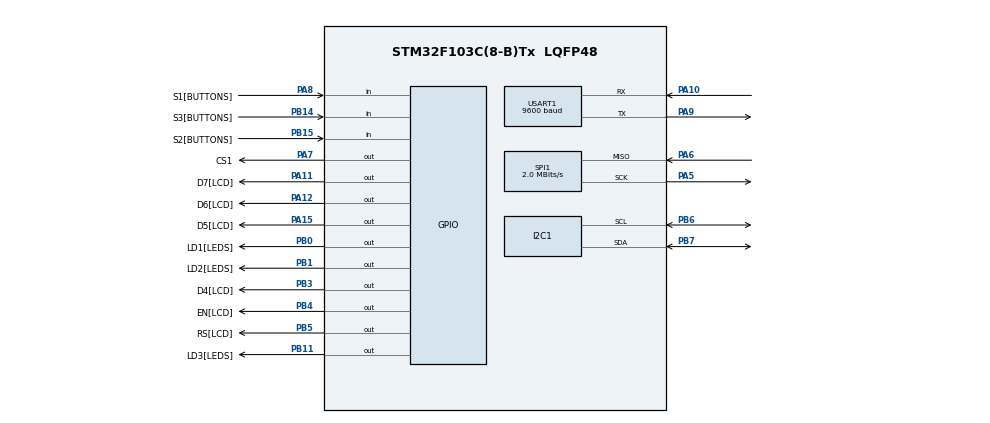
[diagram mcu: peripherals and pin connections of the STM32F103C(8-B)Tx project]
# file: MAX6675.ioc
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I2C1.I2C_Mode=I2C_Standard
Mcu.Family=STM32F1
Mcu.Name=STM32F103C(8-B)Tx
Mcu.Package=LQFP48
NVIC.PriorityGroup=NVIC_PRIORITYGROUP_4
PA10.Mode=Asynchronous
PA10.Signal=USART1_RX
PA11.GPIO_Label=D7[LCD]
PA11.Signal=GPIO_Output
PA12.GPIO_Label=D6[LCD]
PA12.Signal=GPIO_Output
PA13.Mode=Serial_Wire
PA13.Signal=SYS_JTMS-SWDIO
PA14.Mode=Serial_Wire
PA14.Signal=SYS_JTCK-SWCLK
PA15.GPIO_Label=D5[LCD]
PA15.Signal=GPIO_Output
PA5.Mode=RX_Only_Simplex_Unidirect_Master
PA5.Signal=SPI1_SCK
PA6.Mode=RX_Only_Simplex_Unidirect_Master
PA6.Signal=SPI1_MISO
PA7.GPIO_Label=CS1
PA7.Signal=GPIO_Output
PA8.GPIO_Label=S1[BUTTONS]
PA8.Signal=GPIO_Input
PA9.Mode=Asynchronous
PA9.Signal=USART1_TX
PB0.GPIO_Label=LD1[LEDS]
PB0.Signal=GPIO_Output
PB1.GPIO_Label=LD2[LEDS]
PB1.Signal=GPIO_Output
PB11.GPIO_Label=LD3[LEDS]
PB11.Signal=GPIO_Output
PB14.GPIO_Label=S3[BUTTONS]
PB14.Signal=GPIO_Input
PB15.GPIO_Label=S2[BUTTONS]
PB15.Signal=GPIO_Input
PB3.GPIO_Label=D4[LCD]
PB3.Signal=GPIO_Output
PB4.GPIO_Label=EN[LCD]
PB4.Signal=GPIO_Output
PB5.GPIO_Label=RS[LCD]
PB5.Signal=GPIO_Output
PB6.Mode=I2C
PB6.Signal=I2C1_SCL
PB7.Mode=I2C
PB7.Signal=I2C1_SDA
ProjectManager.HeapSize=0x200
ProjectManager.StackSize=0x400
ProjectManager.TargetToolchain=TrueSTUDIO
RCC.AHBFreq_Value=8000000
RCC.APB1Freq_Value=8000000
RCC.APB1TimFreq_Value=8000000
RCC.APB2CLKDivider=RCC_HCLK_DIV2
RCC.APB2Freq_Value=4000000
RCC.APB2TimFreq_Value=8000000
RCC.HCLKFreq_Value=8000000
RCC.PLLMUL=RCC_PLL_MUL9
RCC.SYSCLKFreq_VALUE=8000000
RCC.USBFreq_Value=36000000
SPI1.CLKPhase=SPI_PHASE_1EDGE
SPI1.CLKPolarity=SPI_POLARITY_LOW
SPI1.CalculateBaudRate=2.0 MBits/s
SPI1.DataSize=SPI_DATASIZE_8BIT
SPI1.Direction=SPI_DIRECTION_2LINES_RXONLY
SPI1.FirstBit=SPI_FIRSTBIT_LSB
SPI1.Mode=SPI_MODE_MASTER
SPI1.VirtualType=VM_MASTER
USART1.BaudRate=9600
USART1.VirtualMode=VM_ASYNC
board=MAX6675

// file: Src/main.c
/**
  ******************************************************************************
  * @file           : main.c
  * @brief          : Main program body
  ******************************************************************************
  ** This notice applies to any and all portions of this file
  * that are not between comment pairs USER CODE BEGIN and
  * USER CODE END. Other portions of this file, whether
  * inserted by the user or by software development tools
  * are owned by their respective copyright owners.
  *
  * COPYRIGHT(c) 2018 STMicroelectronics
  *
  * Redistribution and use in source and binary forms, with or without modification,
  * are permitted provided that the following conditions are met:
  *   1. Redistributions of source code must retain the above copyright notice,
  *      this list of conditions and the following disclaimer.
  *   2. Redistributions in binary form must reproduce the above copyright notice,
  *      this list of conditions and the following disclaimer in the documentation
  *      and/or other materials provided with the distribution.
  *   3. Neither the name of STMicroelectronics nor the names of its contributors
  *      may be used to endorse or promote products derived from this software
  *      without specific prior written permission.
  *
  * THIS SOFTWARE IS PROVIDED BY THE COPYRIGHT HOLDERS AND CONTRIBUTORS "AS IS"
  * AND ANY EXPRESS OR IMPLIED WARRANTIES, INCLUDING, BUT NOT LIMITED TO, THE
  * IMPLIED WARRANTIES OF MERCHANTABILITY AND FITNESS FOR A PARTICULAR PURPOSE ARE
  * DISCLAIMED. IN NO EVENT SHALL THE COPYRIGHT HOLDER OR CONTRIBUTORS BE LIABLE
  * FOR ANY DIRECT, INDIRECT, INCIDENTAL, SPECIAL, EXEMPLARY, OR CONSEQUENTIAL
  * DAMAGES (INCLUDING, BUT NOT LIMITED TO, PROCUREMENT OF SUBSTITUTE GOODS OR
  * SERVICES; LOSS OF USE, DATA, OR PROFITS; OR BUSINESS INTERRUPTION) HOWEVER
  * CAUSED AND ON ANY THEORY OF LIABILITY, WHETHER IN CONTRACT, STRICT LIABILITY,
  * OR TORT (INCLUDING NEGLIGENCE OR OTHERWISE) ARISING IN ANY WAY OUT OF THE USE
  * OF THIS SOFTWARE, EVEN IF ADVISED OF THE POSSIBILITY OF SUCH DAMAGE.
  *
  ******************************************************************************
  */
#include "main.h"
#include "stm32f1xx_hal.h"

/* USER CODE BEGIN Includes */

#include <stdio.h>
#include <stdlib.h>

/* USER CODE END Includes */

I2C_HandleTypeDef hi2c1;

SPI_HandleTypeDef hspi1;

UART_HandleTypeDef huart1;

/* USER CODE BEGIN PV */
/* Private variables ---------------------------------------------------------*/

// defines MAX6675 ADDRES
#define MAX6675_SPI     &hspi1

// functios CS
#define MAX6675_CS_SET()   ( HAL_GPIO_WritePin(CS1_GPIO_Port,CS1_Pin,GPIO_PIN_RESET))
#define MAX6675_CS_RESET() (HAL_GPIO_WritePin(CS1_GPIO_Port,CS1_Pin,GPIO_PIN_SET))

// ERROS STATUS
#define MAX6675_OK      1
#define MAX6675_ERROR   0

uint8_t data[2],i=0;

uint8_t Cmd[1] = {10};

 uint32_t D2;
 uint8_t outputBuffer[2] = {0xFF,0x0F};

 char buffer[10];
 char buff[10];
 uint16_t temperature,temp1;
 float temp,current_temp,final_temp;

 uint8_t answer = 0;
 uint16_t reg = 0;
 float temper = 0;
char string[15] = {0};

/* USER CODE END PV */

void SystemClock_Config(void);
static void MX_GPIO_Init(void);
static void MX_I2C1_Init(void);
static void MX_SPI1_Init(void);
static void MX_USART1_UART_Init(void);

/* USER CODE BEGIN PFP */
/* Private function prototypes -----------------------------------------------*/

/* USER CODE END PFP */

/* USER CODE BEGIN 0 */

void write_lcd (uint8_t data, uint8_t cmd_data)
{
	// identifica comando ou dado
	if (cmd_data) HAL_GPIO_WritePin(RS_GPIO_Port, RS_Pin, GPIO_PIN_SET);
	else 					HAL_GPIO_WritePin(RS_GPIO_Port, RS_Pin, GPIO_PIN_RESET);

	// 4 bits high
	if (data & 0x80) HAL_GPIO_WritePin (D7_GPIO_Port, D7_Pin, GPIO_PIN_SET);
	else						 HAL_GPIO_WritePin (D7_GPIO_Port, D7_Pin, GPIO_PIN_RESET);
	if (data & 0x40) HAL_GPIO_WritePin (D6_GPIO_Port, D6_Pin, GPIO_PIN_SET);
	else						 HAL_GPIO_WritePin (D6_GPIO_Port, D6_Pin, GPIO_PIN_RESET);
	if (data & 0x20) HAL_GPIO_WritePin (D5_GPIO_Port, D5_Pin, GPIO_PIN_SET);
	else						 HAL_GPIO_WritePin (D5_GPIO_Port, D5_Pin, GPIO_PIN_RESET);
	if (data & 0x10) HAL_GPIO_WritePin (D4_GPIO_Port, D4_Pin, GPIO_PIN_SET);
	else						 HAL_GPIO_WritePin (D4_GPIO_Port, D4_Pin, GPIO_PIN_RESET);

	HAL_GPIO_WritePin(EN_GPIO_Port, EN_Pin, GPIO_PIN_SET);
	HAL_Delay(2);
	HAL_GPIO_WritePin(EN_GPIO_Port, EN_Pin, GPIO_PIN_RESET);

	// 4 bits Low
	if (data & 0x08) HAL_GPIO_WritePin (D7_GPIO_Port, D7_Pin, GPIO_PIN_SET);
	else						 HAL_GPIO_WritePin (D7_GPIO_Port, D7_Pin, GPIO_PIN_RESET);
	if (data & 0x04) HAL_GPIO_WritePin (D6_GPIO_Port, D6_Pin, GPIO_PIN_SET);
	else						 HAL_GPIO_WritePin (D6_GPIO_Port, D6_Pin, GPIO_PIN_RESET);
	if (data & 0x02) HAL_GPIO_WritePin (D5_GPIO_Port, D5_Pin, GPIO_PIN_SET);
	else						 HAL_GPIO_WritePin (D5_GPIO_Port, D5_Pin, GPIO_PIN_RESET);
	if (data & 0x01) HAL_GPIO_WritePin (D4_GPIO_Port, D4_Pin, GPIO_PIN_SET);
	else						 HAL_GPIO_WritePin (D4_GPIO_Port, D4_Pin, GPIO_PIN_RESET);

	HAL_GPIO_WritePin(EN_GPIO_Port, EN_Pin, GPIO_PIN_SET);
	HAL_Delay(2);
	HAL_GPIO_WritePin(EN_GPIO_Port, EN_Pin, GPIO_PIN_RESET);
}

/* init_LCD - Inicializa o display em 4bits */
void init_lcd(void)
{
	write_lcd(0x33, 0);
	write_lcd(0x32, 0);
	write_lcd(0x28, 0);
	write_lcd(0x06, 0);
	write_lcd(0x0C, 0);
	write_lcd(0x01, 0);
}

/* string_lcd - escreve string no LCD */
void string_lcd (char *string)
{
	while(*string) write_lcd(*string++, 1);
}

/* USER CODE END 0 */

int main(void)
{

  /* MCU Configuration----------------------------------------------------------*/

  /* Reset of all peripherals, Initializes the Flash interface and the Systick. */
  HAL_Init();

  /* Configure the system clock */
  SystemClock_Config();

  /* Initialize all configured peripherals */
  MX_GPIO_Init();
  MX_I2C1_Init();
  MX_SPI1_Init();
  MX_USART1_UART_Init();
  /* USER CODE BEGIN 2 */
  init_lcd();
  write_lcd(0x84,0);
  string_lcd("DSF 2018");
  write_lcd(0xC5,0);
  string_lcd("LNNANO");
  HAL_GPIO_WritePin(CS1_GPIO_Port,CS1_Pin,GPIO_PIN_RESET);
  HAL_Delay(2);
  HAL_SPI_Receive(&hspi1,data,2,200);
  HAL_GPIO_WritePin(CS1_GPIO_Port,CS1_Pin,GPIO_PIN_SET);
  temperature = (uint16_t)(data[0] >> 3);
  temperature |= (uint16_t)(data[1] << 5);
  temp = temperature* 0.25;
  final_temp=temp;
  write_lcd(0x01,0);

  /* USER CODE END 2 */

  /* Infinite loop */
  while (1)
  {

  /* USER CODE BEGIN 3 */

	 if(data[0]&0x01||data[0]&0x04)
	 {
		 write_lcd(0x80,0);
		 string_lcd("#TEMP_ERROR#");
		 do{
			 	 HAL_GPIO_WritePin(CS1_GPIO_Port,CS1_Pin,GPIO_PIN_RESET);
			     HAL_Delay(1);
			     HAL_SPI_Receive(&hspi1,data,2,200);
			     HAL_GPIO_WritePin(CS1_GPIO_Port,CS1_Pin,GPIO_PIN_SET);
		 }
		 while(data[0]&0x01||data[0]&0x04);
		 write_lcd(0x01,0);
	 }
	// for(i=1;i<=100;i++){
     HAL_GPIO_WritePin(CS1_GPIO_Port,CS1_Pin,GPIO_PIN_RESET);
     HAL_Delay(2);
     HAL_GPIO_WritePin(CS1_GPIO_Port,CS1_Pin,GPIO_PIN_SET);
     HAL_Delay(220);
     HAL_GPIO_WritePin(CS1_GPIO_Port,CS1_Pin,GPIO_PIN_RESET);
     HAL_SPI_Receive(&hspi1,data,2,HAL_MAX_DELAY);
     HAL_GPIO_WritePin(CS1_GPIO_Port,CS1_Pin,GPIO_PIN_SET);
	 temperature = (uint16_t)(data[0] >> 3);
	 temperature |= (uint16_t)(data[1] << 5);
	 temp = temperature* 0.25;
	// current_temp+=temp;}
	// current_temp=current_temp/100;
	 if( temp<(final_temp-0.25) || temp>(final_temp+0.25 ) )
	 {
	 final_temp=temp;
	 sprintf(buffer,"%2.2f",temp);
	 write_lcd(0x80,0);
	 string_lcd(buffer);
	 sprintf(buff,"%c",0xdf);
	 write_lcd(0x85,0);
	 string_lcd(buff);
	 write_lcd(0x86,0);
	 string_lcd("C");
	 }
	  HAL_Delay(200);

  }
  /* USER CODE END 3 */

}

void SystemClock_Config(void)
{

  RCC_OscInitTypeDef RCC_OscInitStruct;
  RCC_ClkInitTypeDef RCC_ClkInitStruct;

    /**Initializes the CPU, AHB and APB busses clocks
    */
  RCC_OscInitStruct.OscillatorType = RCC_OSCILLATORTYPE_HSI;
  RCC_OscInitStruct.HSIState = RCC_HSI_ON;
  RCC_OscInitStruct.HSICalibrationValue = 16;
  RCC_OscInitStruct.PLL.PLLState = RCC_PLL_NONE;
  if (HAL_RCC_OscConfig(&RCC_OscInitStruct) != HAL_OK)
  {
    _Error_Handler(__FILE__, __LINE__);
  }

    /**Initializes the CPU, AHB and APB busses clocks
    */
  RCC_ClkInitStruct.ClockType = RCC_CLOCKTYPE_HCLK|RCC_CLOCKTYPE_SYSCLK
                              |RCC_CLOCKTYPE_PCLK1|RCC_CLOCKTYPE_PCLK2;
  RCC_ClkInitStruct.SYSCLKSource = RCC_SYSCLKSOURCE_HSI;
  RCC_ClkInitStruct.AHBCLKDivider = RCC_SYSCLK_DIV1;
  RCC_ClkInitStruct.APB1CLKDivider = RCC_HCLK_DIV1;
  RCC_ClkInitStruct.APB2CLKDivider = RCC_HCLK_DIV4;

  if (HAL_RCC_ClockConfig(&RCC_ClkInitStruct, FLASH_LATENCY_0) != HAL_OK)
  {
    _Error_Handler(__FILE__, __LINE__);
  }

    /**Configure the Systick interrupt time
    */
  HAL_SYSTICK_Config(HAL_RCC_GetHCLKFreq()/1000);

    /**Configure the Systick
    */
  HAL_SYSTICK_CLKSourceConfig(SYSTICK_CLKSOURCE_HCLK);

  /* SysTick_IRQn interrupt configuration */
  HAL_NVIC_SetPriority(SysTick_IRQn, 0, 0);
}

/* I2C1 init function */
static void MX_I2C1_Init(void)
{

  hi2c1.Instance = I2C1;
  hi2c1.Init.ClockSpeed = 100000;
  hi2c1.Init.DutyCycle = I2C_DUTYCYCLE_2;
  hi2c1.Init.OwnAddress1 = 0;
  hi2c1.Init.AddressingMode = I2C_ADDRESSINGMODE_7BIT;
  hi2c1.Init.DualAddressMode = I2C_DUALADDRESS_DISABLE;
  hi2c1.Init.OwnAddress2 = 0;
  hi2c1.Init.GeneralCallMode = I2C_GENERALCALL_DISABLE;
  hi2c1.Init.NoStretchMode = I2C_NOSTRETCH_DISABLE;
  if (HAL_I2C_Init(&hi2c1) != HAL_OK)
  {
    _Error_Handler(__FILE__, __LINE__);
  }

}

/* SPI1 init function */
static void MX_SPI1_Init(void)
{

  /* SPI1 parameter configuration*/
  hspi1.Instance = SPI1;
  hspi1.Init.Mode = SPI_MODE_MASTER;
  hspi1.Init.Direction = SPI_DIRECTION_2LINES_RXONLY;
  hspi1.Init.DataSize = SPI_DATASIZE_8BIT;
  hspi1.Init.CLKPolarity = SPI_POLARITY_LOW;
  hspi1.Init.CLKPhase = SPI_PHASE_1EDGE;
  hspi1.Init.NSS = SPI_NSS_SOFT;
  hspi1.Init.BaudRatePrescaler = SPI_BAUDRATEPRESCALER_2;
  hspi1.Init.FirstBit = SPI_FIRSTBIT_MSB;
  hspi1.Init.TIMode = SPI_TIMODE_DISABLE;
  hspi1.Init.CRCCalculation = SPI_CRCCALCULATION_DISABLE;
  hspi1.Init.CRCPolynomial = 10;
  if (HAL_SPI_Init(&hspi1) != HAL_OK)
  {
    _Error_Handler(__FILE__, __LINE__);
  }

}

/* USART1 init function */
static void MX_USART1_UART_Init(void)
{

  huart1.Instance = USART1;
  huart1.Init.BaudRate = 9600;
  huart1.Init.WordLength = UART_WORDLENGTH_8B;
  huart1.Init.StopBits = UART_STOPBITS_1;
  huart1.Init.Parity = UART_PARITY_NONE;
  huart1.Init.Mode = UART_MODE_TX_RX;
  huart1.Init.HwFlowCtl = UART_HWCONTROL_NONE;
  huart1.Init.OverSampling = UART_OVERSAMPLING_16;
  if (HAL_UART_Init(&huart1) != HAL_OK)
  {
    _Error_Handler(__FILE__, __LINE__);
  }

}

/** Configure pins as
        * Analog
        * Input
        * Output
        * EVENT_OUT
        * EXTI
*/
static void MX_GPIO_Init(void)
{

  GPIO_InitTypeDef GPIO_InitStruct;

  /* GPIO Ports Clock Enable */
  __HAL_RCC_GPIOA_CLK_ENABLE();
  __HAL_RCC_GPIOB_CLK_ENABLE();

  /*Configure GPIO pin Output Level */
  HAL_GPIO_WritePin(GPIOA, CS1_Pin|D7_Pin|D6_Pin|D5_Pin, GPIO_PIN_RESET);

  /*Configure GPIO pin Output Level */
  HAL_GPIO_WritePin(GPIOB, LD1_Pin|LD2_Pin|LD3_Pin|D4_Pin
                          |EN_Pin|RS_Pin, GPIO_PIN_RESET);

  /*Configure GPIO pins : CS1_Pin D7_Pin D6_Pin D5_Pin */
  GPIO_InitStruct.Pin = CS1_Pin|D7_Pin|D6_Pin|D5_Pin;
  GPIO_InitStruct.Mode = GPIO_MODE_OUTPUT_PP;
  GPIO_InitStruct.Speed = GPIO_SPEED_FREQ_LOW;
  HAL_GPIO_Init(GPIOA, &GPIO_InitStruct);

  /*Configure GPIO pins : LD1_Pin LD2_Pin LD3_Pin D4_Pin
                           EN_Pin RS_Pin */
  GPIO_InitStruct.Pin = LD1_Pin|LD2_Pin|LD3_Pin|D4_Pin
                          |EN_Pin|RS_Pin;
  GPIO_InitStruct.Mode = GPIO_MODE_OUTPUT_PP;
  GPIO_InitStruct.Speed = GPIO_SPEED_FREQ_LOW;
  HAL_GPIO_Init(GPIOB, &GPIO_InitStruct);

  /*Configure GPIO pins : S3_Pin S2_Pin */
  GPIO_InitStruct.Pin = S3_Pin|S2_Pin;
  GPIO_InitStruct.Mode = GPIO_MODE_INPUT;
  GPIO_InitStruct.Pull = GPIO_NOPULL;
  HAL_GPIO_Init(GPIOB, &GPIO_InitStruct);

  /*Configure GPIO pin : S1_Pin */
  GPIO_InitStruct.Pin = S1_Pin;
  GPIO_InitStruct.Mode = GPIO_MODE_INPUT;
  GPIO_InitStruct.Pull = GPIO_NOPULL;
  HAL_GPIO_Init(S1_GPIO_Port, &GPIO_InitStruct);

}

void _Error_Handler(char *file, int line)
{
  while(1)
  {
  }
}

/************************ (C) COPYRIGHT STMicroelectronics *****END OF FILE****/
